# Generated by FakeRAM 2.0
VERSION 5.7 ;
BUSBITCHARS "[]" ;
PROPERTYDEFINITIONS
  MACRO width INTEGER ;
  MACRO depth INTEGER ;
  MACRO banks INTEGER ;
END PROPERTYDEFINITIONS
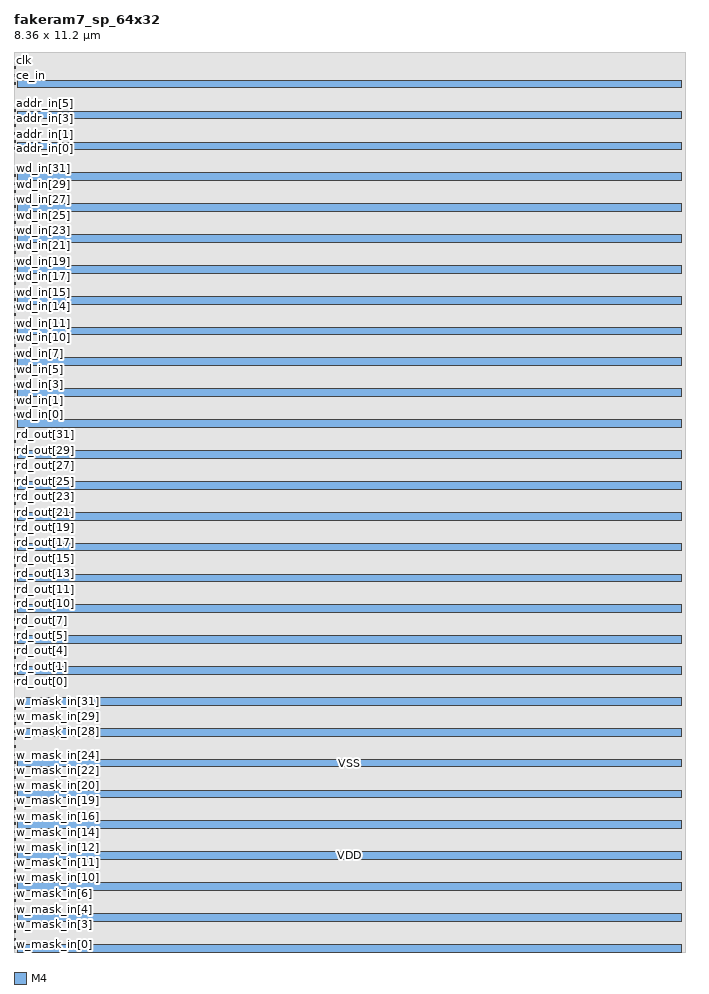
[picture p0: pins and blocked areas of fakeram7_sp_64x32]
MACRO fakeram7_sp_64x32
  PROPERTY width 32 ;
  PROPERTY depth 64 ;
  PROPERTY banks 2 ;
  FOREIGN fakeram7_sp_64x32 0 0 ;
  SYMMETRY X Y ;
  SIZE 8.360 BY 11.200 ;
  CLASS BLOCK ;
  PIN w_mask_in[0]
    DIRECTION INPUT ;
    USE SIGNAL ;
    SHAPE ABUTMENT ;
    PORT
      LAYER M4 ;
      RECT 0.000 0.048 0.024 0.072 ;
    END
  END w_mask_in[0]
  PIN w_mask_in[1]
    DIRECTION INPUT ;
    USE SIGNAL ;
    SHAPE ABUTMENT ;
    PORT
      LAYER M4 ;
      RECT 0.000 0.144 0.024 0.168 ;
    END
  END w_mask_in[1]
  PIN w_mask_in[2]
    DIRECTION INPUT ;
    USE SIGNAL ;
    SHAPE ABUTMENT ;
    PORT
      LAYER M4 ;
      RECT 0.000 0.240 0.024 0.264 ;
    END
  END w_mask_in[2]
  PIN w_mask_in[3]
    DIRECTION INPUT ;
    USE SIGNAL ;
    SHAPE ABUTMENT ;
    PORT
      LAYER M4 ;
      RECT 0.000 0.336 0.024 0.360 ;
    END
  END w_mask_in[3]
  PIN w_mask_in[4]
    DIRECTION INPUT ;
    USE SIGNAL ;
    SHAPE ABUTMENT ;
    PORT
      LAYER M4 ;
      RECT 0.000 0.432 0.024 0.456 ;
    END
  END w_mask_in[4]
  PIN w_mask_in[5]
    DIRECTION INPUT ;
    USE SIGNAL ;
    SHAPE ABUTMENT ;
    PORT
      LAYER M4 ;
      RECT 0.000 0.528 0.024 0.552 ;
    END
  END w_mask_in[5]
  PIN w_mask_in[6]
    DIRECTION INPUT ;
    USE SIGNAL ;
    SHAPE ABUTMENT ;
    PORT
      LAYER M4 ;
      RECT 0.000 0.624 0.024 0.648 ;
    END
  END w_mask_in[6]
  PIN w_mask_in[7]
    DIRECTION INPUT ;
    USE SIGNAL ;
    SHAPE ABUTMENT ;
    PORT
      LAYER M4 ;
      RECT 0.000 0.720 0.024 0.744 ;
    END
  END w_mask_in[7]
  PIN w_mask_in[8]
    DIRECTION INPUT ;
    USE SIGNAL ;
    SHAPE ABUTMENT ;
    PORT
      LAYER M4 ;
      RECT 0.000 0.816 0.024 0.840 ;
    END
  END w_mask_in[8]
  PIN w_mask_in[9]
    DIRECTION INPUT ;
    USE SIGNAL ;
    SHAPE ABUTMENT ;
    PORT
      LAYER M4 ;
      RECT 0.000 0.912 0.024 0.936 ;
    END
  END w_mask_in[9]
  PIN w_mask_in[10]
    DIRECTION INPUT ;
    USE SIGNAL ;
    SHAPE ABUTMENT ;
    PORT
      LAYER M4 ;
      RECT 0.000 1.008 0.024 1.032 ;
    END
  END w_mask_in[10]
  PIN w_mask_in[11]
    DIRECTION INPUT ;
    USE SIGNAL ;
    SHAPE ABUTMENT ;
    PORT
      LAYER M4 ;
      RECT 0.000 1.104 0.024 1.128 ;
    END
  END w_mask_in[11]
  PIN w_mask_in[12]
    DIRECTION INPUT ;
    USE SIGNAL ;
    SHAPE ABUTMENT ;
    PORT
      LAYER M4 ;
      RECT 0.000 1.200 0.024 1.224 ;
    END
  END w_mask_in[12]
  PIN w_mask_in[13]
    DIRECTION INPUT ;
    USE SIGNAL ;
    SHAPE ABUTMENT ;
    PORT
      LAYER M4 ;
      RECT 0.000 1.296 0.024 1.320 ;
    END
  END w_mask_in[13]
  PIN w_mask_in[14]
    DIRECTION INPUT ;
    USE SIGNAL ;
    SHAPE ABUTMENT ;
    PORT
      LAYER M4 ;
      RECT 0.000 1.392 0.024 1.416 ;
    END
  END w_mask_in[14]
  PIN w_mask_in[15]
    DIRECTION INPUT ;
    USE SIGNAL ;
    SHAPE ABUTMENT ;
    PORT
      LAYER M4 ;
      RECT 0.000 1.488 0.024 1.512 ;
    END
  END w_mask_in[15]
  PIN w_mask_in[16]
    DIRECTION INPUT ;
    USE SIGNAL ;
    SHAPE ABUTMENT ;
    PORT
      LAYER M4 ;
      RECT 0.000 1.584 0.024 1.608 ;
    END
  END w_mask_in[16]
  PIN w_mask_in[17]
    DIRECTION INPUT ;
    USE SIGNAL ;
    SHAPE ABUTMENT ;
    PORT
      LAYER M4 ;
      RECT 0.000 1.680 0.024 1.704 ;
    END
  END w_mask_in[17]
  PIN w_mask_in[18]
    DIRECTION INPUT ;
    USE SIGNAL ;
    SHAPE ABUTMENT ;
    PORT
      LAYER M4 ;
      RECT 0.000 1.776 0.024 1.800 ;
    END
  END w_mask_in[18]
  PIN w_mask_in[19]
    DIRECTION INPUT ;
    USE SIGNAL ;
    SHAPE ABUTMENT ;
    PORT
      LAYER M4 ;
      RECT 0.000 1.872 0.024 1.896 ;
    END
  END w_mask_in[19]
  PIN w_mask_in[20]
    DIRECTION INPUT ;
    USE SIGNAL ;
    SHAPE ABUTMENT ;
    PORT
      LAYER M4 ;
      RECT 0.000 1.968 0.024 1.992 ;
    END
  END w_mask_in[20]
  PIN w_mask_in[21]
    DIRECTION INPUT ;
    USE SIGNAL ;
    SHAPE ABUTMENT ;
    PORT
      LAYER M4 ;
      RECT 0.000 2.064 0.024 2.088 ;
    END
  END w_mask_in[21]
  PIN w_mask_in[22]
    DIRECTION INPUT ;
    USE SIGNAL ;
    SHAPE ABUTMENT ;
    PORT
      LAYER M4 ;
      RECT 0.000 2.160 0.024 2.184 ;
    END
  END w_mask_in[22]
  PIN w_mask_in[23]
    DIRECTION INPUT ;
    USE SIGNAL ;
    SHAPE ABUTMENT ;
    PORT
      LAYER M4 ;
      RECT 0.000 2.256 0.024 2.280 ;
    END
  END w_mask_in[23]
  PIN w_mask_in[24]
    DIRECTION INPUT ;
    USE SIGNAL ;
    SHAPE ABUTMENT ;
    PORT
      LAYER M4 ;
      RECT 0.000 2.352 0.024 2.376 ;
    END
  END w_mask_in[24]
  PIN w_mask_in[25]
    DIRECTION INPUT ;
    USE SIGNAL ;
    SHAPE ABUTMENT ;
    PORT
      LAYER M4 ;
      RECT 0.000 2.448 0.024 2.472 ;
    END
  END w_mask_in[25]
  PIN w_mask_in[26]
    DIRECTION INPUT ;
    USE SIGNAL ;
    SHAPE ABUTMENT ;
    PORT
      LAYER M4 ;
      RECT 0.000 2.544 0.024 2.568 ;
    END
  END w_mask_in[26]
  PIN w_mask_in[27]
    DIRECTION INPUT ;
    USE SIGNAL ;
    SHAPE ABUTMENT ;
    PORT
      LAYER M4 ;
      RECT 0.000 2.640 0.024 2.664 ;
    END
  END w_mask_in[27]
  PIN w_mask_in[28]
    DIRECTION INPUT ;
    USE SIGNAL ;
    SHAPE ABUTMENT ;
    PORT
      LAYER M4 ;
      RECT 0.000 2.736 0.024 2.760 ;
    END
  END w_mask_in[28]
  PIN w_mask_in[29]
    DIRECTION INPUT ;
    USE SIGNAL ;
    SHAPE ABUTMENT ;
    PORT
      LAYER M4 ;
      RECT 0.000 2.832 0.024 2.856 ;
    END
  END w_mask_in[29]
  PIN w_mask_in[30]
    DIRECTION INPUT ;
    USE SIGNAL ;
    SHAPE ABUTMENT ;
    PORT
      LAYER M4 ;
      RECT 0.000 2.928 0.024 2.952 ;
    END
  END w_mask_in[30]
  PIN w_mask_in[31]
    DIRECTION INPUT ;
    USE SIGNAL ;
    SHAPE ABUTMENT ;
    PORT
      LAYER M4 ;
      RECT 0.000 3.024 0.024 3.048 ;
    END
  END w_mask_in[31]
  PIN rd_out[0]
    DIRECTION OUTPUT ;
    USE SIGNAL ;
    SHAPE ABUTMENT ;
    PORT
      LAYER M4 ;
      RECT 0.000 3.360 0.024 3.384 ;
    END
  END rd_out[0]
  PIN rd_out[1]
    DIRECTION OUTPUT ;
    USE SIGNAL ;
    SHAPE ABUTMENT ;
    PORT
      LAYER M4 ;
      RECT 0.000 3.456 0.024 3.480 ;
    END
  END rd_out[1]
  PIN rd_out[2]
    DIRECTION OUTPUT ;
    USE SIGNAL ;
    SHAPE ABUTMENT ;
    PORT
      LAYER M4 ;
      RECT 0.000 3.552 0.024 3.576 ;
    END
  END rd_out[2]
  PIN rd_out[3]
    DIRECTION OUTPUT ;
    USE SIGNAL ;
    SHAPE ABUTMENT ;
    PORT
      LAYER M4 ;
      RECT 0.000 3.648 0.024 3.672 ;
    END
  END rd_out[3]
  PIN rd_out[4]
    DIRECTION OUTPUT ;
    USE SIGNAL ;
    SHAPE ABUTMENT ;
    PORT
      LAYER M4 ;
      RECT 0.000 3.744 0.024 3.768 ;
    END
  END rd_out[4]
  PIN rd_out[5]
    DIRECTION OUTPUT ;
    USE SIGNAL ;
    SHAPE ABUTMENT ;
    PORT
      LAYER M4 ;
      RECT 0.000 3.840 0.024 3.864 ;
    END
  END rd_out[5]
  PIN rd_out[6]
    DIRECTION OUTPUT ;
    USE SIGNAL ;
    SHAPE ABUTMENT ;
    PORT
      LAYER M4 ;
      RECT 0.000 3.936 0.024 3.960 ;
    END
  END rd_out[6]
  PIN rd_out[7]
    DIRECTION OUTPUT ;
    USE SIGNAL ;
    SHAPE ABUTMENT ;
    PORT
      LAYER M4 ;
      RECT 0.000 4.032 0.024 4.056 ;
    END
  END rd_out[7]
  PIN rd_out[8]
    DIRECTION OUTPUT ;
    USE SIGNAL ;
    SHAPE ABUTMENT ;
    PORT
      LAYER M4 ;
      RECT 0.000 4.128 0.024 4.152 ;
    END
  END rd_out[8]
  PIN rd_out[9]
    DIRECTION OUTPUT ;
    USE SIGNAL ;
    SHAPE ABUTMENT ;
    PORT
      LAYER M4 ;
      RECT 0.000 4.224 0.024 4.248 ;
    END
  END rd_out[9]
  PIN rd_out[10]
    DIRECTION OUTPUT ;
    USE SIGNAL ;
    SHAPE ABUTMENT ;
    PORT
      LAYER M4 ;
      RECT 0.000 4.320 0.024 4.344 ;
    END
  END rd_out[10]
  PIN rd_out[11]
    DIRECTION OUTPUT ;
    USE SIGNAL ;
    SHAPE ABUTMENT ;
    PORT
      LAYER M4 ;
      RECT 0.000 4.416 0.024 4.440 ;
    END
  END rd_out[11]
  PIN rd_out[12]
    DIRECTION OUTPUT ;
    USE SIGNAL ;
    SHAPE ABUTMENT ;
    PORT
      LAYER M4 ;
      RECT 0.000 4.512 0.024 4.536 ;
    END
  END rd_out[12]
  PIN rd_out[13]
    DIRECTION OUTPUT ;
    USE SIGNAL ;
    SHAPE ABUTMENT ;
    PORT
      LAYER M4 ;
      RECT 0.000 4.608 0.024 4.632 ;
    END
  END rd_out[13]
  PIN rd_out[14]
    DIRECTION OUTPUT ;
    USE SIGNAL ;
    SHAPE ABUTMENT ;
    PORT
      LAYER M4 ;
      RECT 0.000 4.704 0.024 4.728 ;
    END
  END rd_out[14]
  PIN rd_out[15]
    DIRECTION OUTPUT ;
    USE SIGNAL ;
    SHAPE ABUTMENT ;
    PORT
      LAYER M4 ;
      RECT 0.000 4.800 0.024 4.824 ;
    END
  END rd_out[15]
  PIN rd_out[16]
    DIRECTION OUTPUT ;
    USE SIGNAL ;
    SHAPE ABUTMENT ;
    PORT
      LAYER M4 ;
      RECT 0.000 4.896 0.024 4.920 ;
    END
  END rd_out[16]
  PIN rd_out[17]
    DIRECTION OUTPUT ;
    USE SIGNAL ;
    SHAPE ABUTMENT ;
    PORT
      LAYER M4 ;
      RECT 0.000 4.992 0.024 5.016 ;
    END
  END rd_out[17]
  PIN rd_out[18]
    DIRECTION OUTPUT ;
    USE SIGNAL ;
    SHAPE ABUTMENT ;
    PORT
      LAYER M4 ;
      RECT 0.000 5.088 0.024 5.112 ;
    END
  END rd_out[18]
  PIN rd_out[19]
    DIRECTION OUTPUT ;
    USE SIGNAL ;
    SHAPE ABUTMENT ;
    PORT
      LAYER M4 ;
      RECT 0.000 5.184 0.024 5.208 ;
    END
  END rd_out[19]
  PIN rd_out[20]
    DIRECTION OUTPUT ;
    USE SIGNAL ;
    SHAPE ABUTMENT ;
    PORT
      LAYER M4 ;
      RECT 0.000 5.280 0.024 5.304 ;
    END
  END rd_out[20]
  PIN rd_out[21]
    DIRECTION OUTPUT ;
    USE SIGNAL ;
    SHAPE ABUTMENT ;
    PORT
      LAYER M4 ;
      RECT 0.000 5.376 0.024 5.400 ;
    END
  END rd_out[21]
  PIN rd_out[22]
    DIRECTION OUTPUT ;
    USE SIGNAL ;
    SHAPE ABUTMENT ;
    PORT
      LAYER M4 ;
      RECT 0.000 5.472 0.024 5.496 ;
    END
  END rd_out[22]
  PIN rd_out[23]
    DIRECTION OUTPUT ;
    USE SIGNAL ;
    SHAPE ABUTMENT ;
    PORT
      LAYER M4 ;
      RECT 0.000 5.568 0.024 5.592 ;
    END
  END rd_out[23]
  PIN rd_out[24]
    DIRECTION OUTPUT ;
    USE SIGNAL ;
    SHAPE ABUTMENT ;
    PORT
      LAYER M4 ;
      RECT 0.000 5.664 0.024 5.688 ;
    END
  END rd_out[24]
  PIN rd_out[25]
    DIRECTION OUTPUT ;
    USE SIGNAL ;
    SHAPE ABUTMENT ;
    PORT
      LAYER M4 ;
      RECT 0.000 5.760 0.024 5.784 ;
    END
  END rd_out[25]
  PIN rd_out[26]
    DIRECTION OUTPUT ;
    USE SIGNAL ;
    SHAPE ABUTMENT ;
    PORT
      LAYER M4 ;
      RECT 0.000 5.856 0.024 5.880 ;
    END
  END rd_out[26]
  PIN rd_out[27]
    DIRECTION OUTPUT ;
    USE SIGNAL ;
    SHAPE ABUTMENT ;
    PORT
      LAYER M4 ;
      RECT 0.000 5.952 0.024 5.976 ;
    END
  END rd_out[27]
  PIN rd_out[28]
    DIRECTION OUTPUT ;
    USE SIGNAL ;
    SHAPE ABUTMENT ;
    PORT
      LAYER M4 ;
      RECT 0.000 6.048 0.024 6.072 ;
    END
  END rd_out[28]
  PIN rd_out[29]
    DIRECTION OUTPUT ;
    USE SIGNAL ;
    SHAPE ABUTMENT ;
    PORT
      LAYER M4 ;
      RECT 0.000 6.144 0.024 6.168 ;
    END
  END rd_out[29]
  PIN rd_out[30]
    DIRECTION OUTPUT ;
    USE SIGNAL ;
    SHAPE ABUTMENT ;
    PORT
      LAYER M4 ;
      RECT 0.000 6.240 0.024 6.264 ;
    END
  END rd_out[30]
  PIN rd_out[31]
    DIRECTION OUTPUT ;
    USE SIGNAL ;
    SHAPE ABUTMENT ;
    PORT
      LAYER M4 ;
      RECT 0.000 6.336 0.024 6.360 ;
    END
  END rd_out[31]
  PIN wd_in[0]
    DIRECTION INPUT ;
    USE SIGNAL ;
    SHAPE ABUTMENT ;
    PORT
      LAYER M4 ;
      RECT 0.000 6.672 0.024 6.696 ;
    END
  END wd_in[0]
  PIN wd_in[1]
    DIRECTION INPUT ;
    USE SIGNAL ;
    SHAPE ABUTMENT ;
    PORT
      LAYER M4 ;
      RECT 0.000 6.768 0.024 6.792 ;
    END
  END wd_in[1]
  PIN wd_in[2]
    DIRECTION INPUT ;
    USE SIGNAL ;
    SHAPE ABUTMENT ;
    PORT
      LAYER M4 ;
      RECT 0.000 6.864 0.024 6.888 ;
    END
  END wd_in[2]
  PIN wd_in[3]
    DIRECTION INPUT ;
    USE SIGNAL ;
    SHAPE ABUTMENT ;
    PORT
      LAYER M4 ;
      RECT 0.000 6.960 0.024 6.984 ;
    END
  END wd_in[3]
  PIN wd_in[4]
    DIRECTION INPUT ;
    USE SIGNAL ;
    SHAPE ABUTMENT ;
    PORT
      LAYER M4 ;
      RECT 0.000 7.056 0.024 7.080 ;
    END
  END wd_in[4]
  PIN wd_in[5]
    DIRECTION INPUT ;
    USE SIGNAL ;
    SHAPE ABUTMENT ;
    PORT
      LAYER M4 ;
      RECT 0.000 7.152 0.024 7.176 ;
    END
  END wd_in[5]
  PIN wd_in[6]
    DIRECTION INPUT ;
    USE SIGNAL ;
    SHAPE ABUTMENT ;
    PORT
      LAYER M4 ;
      RECT 0.000 7.248 0.024 7.272 ;
    END
  END wd_in[6]
  PIN wd_in[7]
    DIRECTION INPUT ;
    USE SIGNAL ;
    SHAPE ABUTMENT ;
    PORT
      LAYER M4 ;
      RECT 0.000 7.344 0.024 7.368 ;
    END
  END wd_in[7]
  PIN wd_in[8]
    DIRECTION INPUT ;
    USE SIGNAL ;
    SHAPE ABUTMENT ;
    PORT
      LAYER M4 ;
      RECT 0.000 7.440 0.024 7.464 ;
    END
  END wd_in[8]
  PIN wd_in[9]
    DIRECTION INPUT ;
    USE SIGNAL ;
    SHAPE ABUTMENT ;
    PORT
      LAYER M4 ;
      RECT 0.000 7.536 0.024 7.560 ;
    END
  END wd_in[9]
  PIN wd_in[10]
    DIRECTION INPUT ;
    USE SIGNAL ;
    SHAPE ABUTMENT ;
    PORT
      LAYER M4 ;
      RECT 0.000 7.632 0.024 7.656 ;
    END
  END wd_in[10]
  PIN wd_in[11]
    DIRECTION INPUT ;
    USE SIGNAL ;
    SHAPE ABUTMENT ;
    PORT
      LAYER M4 ;
      RECT 0.000 7.728 0.024 7.752 ;
    END
  END wd_in[11]
  PIN wd_in[12]
    DIRECTION INPUT ;
    USE SIGNAL ;
    SHAPE ABUTMENT ;
    PORT
      LAYER M4 ;
      RECT 0.000 7.824 0.024 7.848 ;
    END
  END wd_in[12]
  PIN wd_in[13]
    DIRECTION INPUT ;
    USE SIGNAL ;
    SHAPE ABUTMENT ;
    PORT
      LAYER M4 ;
      RECT 0.000 7.920 0.024 7.944 ;
    END
  END wd_in[13]
  PIN wd_in[14]
    DIRECTION INPUT ;
    USE SIGNAL ;
    SHAPE ABUTMENT ;
    PORT
      LAYER M4 ;
      RECT 0.000 8.016 0.024 8.040 ;
    END
  END wd_in[14]
  PIN wd_in[15]
    DIRECTION INPUT ;
    USE SIGNAL ;
    SHAPE ABUTMENT ;
    PORT
      LAYER M4 ;
      RECT 0.000 8.112 0.024 8.136 ;
    END
  END wd_in[15]
  PIN wd_in[16]
    DIRECTION INPUT ;
    USE SIGNAL ;
    SHAPE ABUTMENT ;
    PORT
      LAYER M4 ;
      RECT 0.000 8.208 0.024 8.232 ;
    END
  END wd_in[16]
  PIN wd_in[17]
    DIRECTION INPUT ;
    USE SIGNAL ;
    SHAPE ABUTMENT ;
    PORT
      LAYER M4 ;
      RECT 0.000 8.304 0.024 8.328 ;
    END
  END wd_in[17]
  PIN wd_in[18]
    DIRECTION INPUT ;
    USE SIGNAL ;
    SHAPE ABUTMENT ;
    PORT
      LAYER M4 ;
      RECT 0.000 8.400 0.024 8.424 ;
    END
  END wd_in[18]
  PIN wd_in[19]
    DIRECTION INPUT ;
    USE SIGNAL ;
    SHAPE ABUTMENT ;
    PORT
      LAYER M4 ;
      RECT 0.000 8.496 0.024 8.520 ;
    END
  END wd_in[19]
  PIN wd_in[20]
    DIRECTION INPUT ;
    USE SIGNAL ;
    SHAPE ABUTMENT ;
    PORT
      LAYER M4 ;
      RECT 0.000 8.592 0.024 8.616 ;
    END
  END wd_in[20]
  PIN wd_in[21]
    DIRECTION INPUT ;
    USE SIGNAL ;
    SHAPE ABUTMENT ;
    PORT
      LAYER M4 ;
      RECT 0.000 8.688 0.024 8.712 ;
    END
  END wd_in[21]
  PIN wd_in[22]
    DIRECTION INPUT ;
    USE SIGNAL ;
    SHAPE ABUTMENT ;
    PORT
      LAYER M4 ;
      RECT 0.000 8.784 0.024 8.808 ;
    END
  END wd_in[22]
  PIN wd_in[23]
    DIRECTION INPUT ;
    USE SIGNAL ;
    SHAPE ABUTMENT ;
    PORT
      LAYER M4 ;
      RECT 0.000 8.880 0.024 8.904 ;
    END
  END wd_in[23]
  PIN wd_in[24]
    DIRECTION INPUT ;
    USE SIGNAL ;
    SHAPE ABUTMENT ;
    PORT
      LAYER M4 ;
      RECT 0.000 8.976 0.024 9.000 ;
    END
  END wd_in[24]
  PIN wd_in[25]
    DIRECTION INPUT ;
    USE SIGNAL ;
    SHAPE ABUTMENT ;
    PORT
      LAYER M4 ;
      RECT 0.000 9.072 0.024 9.096 ;
    END
  END wd_in[25]
  PIN wd_in[26]
    DIRECTION INPUT ;
    USE SIGNAL ;
    SHAPE ABUTMENT ;
    PORT
      LAYER M4 ;
      RECT 0.000 9.168 0.024 9.192 ;
    END
  END wd_in[26]
  PIN wd_in[27]
    DIRECTION INPUT ;
    USE SIGNAL ;
    SHAPE ABUTMENT ;
    PORT
      LAYER M4 ;
      RECT 0.000 9.264 0.024 9.288 ;
    END
  END wd_in[27]
  PIN wd_in[28]
    DIRECTION INPUT ;
    USE SIGNAL ;
    SHAPE ABUTMENT ;
    PORT
      LAYER M4 ;
      RECT 0.000 9.360 0.024 9.384 ;
    END
  END wd_in[28]
  PIN wd_in[29]
    DIRECTION INPUT ;
    USE SIGNAL ;
    SHAPE ABUTMENT ;
    PORT
      LAYER M4 ;
      RECT 0.000 9.456 0.024 9.480 ;
    END
  END wd_in[29]
  PIN wd_in[30]
    DIRECTION INPUT ;
    USE SIGNAL ;
    SHAPE ABUTMENT ;
    PORT
      LAYER M4 ;
      RECT 0.000 9.552 0.024 9.576 ;
    END
  END wd_in[30]
  PIN wd_in[31]
    DIRECTION INPUT ;
    USE SIGNAL ;
    SHAPE ABUTMENT ;
    PORT
      LAYER M4 ;
      RECT 0.000 9.648 0.024 9.672 ;
    END
  END wd_in[31]
  PIN addr_in[0]
    DIRECTION INPUT ;
    USE SIGNAL ;
    SHAPE ABUTMENT ;
    PORT
      LAYER M4 ;
      RECT 0.000 9.984 0.024 10.008 ;
    END
  END addr_in[0]
  PIN addr_in[1]
    DIRECTION INPUT ;
    USE SIGNAL ;
    SHAPE ABUTMENT ;
    PORT
      LAYER M4 ;
      RECT 0.000 10.080 0.024 10.104 ;
    END
  END addr_in[1]
  PIN addr_in[2]
    DIRECTION INPUT ;
    USE SIGNAL ;
    SHAPE ABUTMENT ;
    PORT
      LAYER M4 ;
      RECT 0.000 10.176 0.024 10.200 ;
    END
  END addr_in[2]
  PIN addr_in[3]
    DIRECTION INPUT ;
    USE SIGNAL ;
    SHAPE ABUTMENT ;
    PORT
      LAYER M4 ;
      RECT 0.000 10.272 0.024 10.296 ;
    END
  END addr_in[3]
  PIN addr_in[4]
    DIRECTION INPUT ;
    USE SIGNAL ;
    SHAPE ABUTMENT ;
    PORT
      LAYER M4 ;
      RECT 0.000 10.368 0.024 10.392 ;
    END
  END addr_in[4]
  PIN addr_in[5]
    DIRECTION INPUT ;
    USE SIGNAL ;
    SHAPE ABUTMENT ;
    PORT
      LAYER M4 ;
      RECT 0.000 10.464 0.024 10.488 ;
    END
  END addr_in[5]
  PIN we_in
    DIRECTION INPUT ;
    USE SIGNAL ;
    SHAPE ABUTMENT ;
    PORT
      LAYER M4 ;
      RECT 0.000 10.800 0.024 10.824 ;
    END
  END we_in
  PIN ce_in
    DIRECTION INPUT ;
    USE SIGNAL ;
    SHAPE ABUTMENT ;
    PORT
      LAYER M4 ;
      RECT 0.000 10.896 0.024 10.920 ;
    END
  END ce_in
  PIN clk
    DIRECTION INPUT ;
    USE SIGNAL ;
    SHAPE ABUTMENT ;
    PORT
      LAYER M4 ;
      RECT 0.000 10.992 0.024 11.016 ;
    END
  END clk
  PIN VSS
    DIRECTION INOUT ;
    USE GROUND ;
    PORT
      LAYER M4 ;
      RECT 0.048 0.000 8.312 0.096 ;
      RECT 0.048 0.768 8.312 0.864 ;
      RECT 0.048 1.536 8.312 1.632 ;
      RECT 0.048 2.304 8.312 2.400 ;
      RECT 0.048 3.072 8.312 3.168 ;
      RECT 0.048 3.840 8.312 3.936 ;
      RECT 0.048 4.608 8.312 4.704 ;
      RECT 0.048 5.376 8.312 5.472 ;
      RECT 0.048 6.144 8.312 6.240 ;
      RECT 0.048 6.912 8.312 7.008 ;
      RECT 0.048 7.680 8.312 7.776 ;
      RECT 0.048 8.448 8.312 8.544 ;
      RECT 0.048 9.216 8.312 9.312 ;
      RECT 0.048 9.984 8.312 10.080 ;
      RECT 0.048 10.752 8.312 10.848 ;
    END
  END VSS
  PIN VDD
    DIRECTION INOUT ;
    USE POWER ;
    PORT
      LAYER M4 ;
      RECT 0.048 0.384 8.312 0.480 ;
      RECT 0.048 1.152 8.312 1.248 ;
      RECT 0.048 1.920 8.312 2.016 ;
      RECT 0.048 2.688 8.312 2.784 ;
      RECT 0.048 3.456 8.312 3.552 ;
      RECT 0.048 4.224 8.312 4.320 ;
      RECT 0.048 4.992 8.312 5.088 ;
      RECT 0.048 5.760 8.312 5.856 ;
      RECT 0.048 6.528 8.312 6.624 ;
      RECT 0.048 7.296 8.312 7.392 ;
      RECT 0.048 8.064 8.312 8.160 ;
      RECT 0.048 8.832 8.312 8.928 ;
      RECT 0.048 9.600 8.312 9.696 ;
      RECT 0.048 10.368 8.312 10.464 ;
    END
  END VDD
  OBS
    LAYER M1 ;
    RECT 0 0 8.360 11.200 ;
    LAYER M2 ;
    RECT 0 0 8.360 11.200 ;
    LAYER M3 ;
    RECT 0 0 8.360 11.200 ;
    LAYER M4 ;
    RECT 0 0 8.360 11.200 ;
  END
END fakeram7_sp_64x32

END LIBRARY
